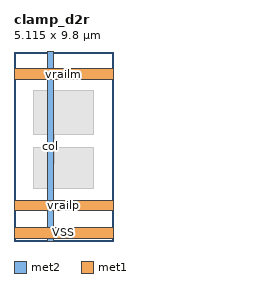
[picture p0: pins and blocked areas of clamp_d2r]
MACRO clamp_d2r
  CLASS BLOCK ;
  ORIGIN 0.000 0.000 ;
  SIZE 5.115 BY 9.800 ;
  SYMMETRY X Y ;
  PIN col
    DIRECTION INOUT ;
    USE SIGNAL ;
    PORT
      LAYER met2 ;
        RECT 1.740 0.000 2.060 9.800 ;
    END
  END col
  PIN vrailp
    DIRECTION INOUT ;
    USE SIGNAL ;
    PORT
      LAYER met1 ;
        RECT 0.000 1.550 5.115 2.100 ;
    END
  END vrailp
  PIN vrailm
    DIRECTION INOUT ;
    USE SIGNAL ;
    PORT
      LAYER met1 ;
        RECT 0.000 8.330 5.115 8.880 ;
    END
  END vrailm
  PIN VSS
    DIRECTION INOUT ;
    USE GROUND ;
    PORT
      LAYER met1 ;
        RECT 0.000 0.150 5.115 0.700 ;
    END
  END VSS
  OBS
    LAYER li1 ;
      RECT 0.250 0.260 4.865 0.590 ;
      RECT 1.000 1.620 4.115 2.040 ;
      RECT 1.000 2.700 4.115 4.805 ;
      RECT 1.735 3.995 2.065 6.305 ;
      RECT 1.000 5.495 4.115 7.745 ;
      RECT 1.000 8.440 4.115 8.770 ;
    LAYER met1 ;
      RECT 0.000 0.150 5.115 0.700 ;
      RECT 0.000 1.550 5.115 2.100 ;
      RECT 1.720 4.970 2.080 5.330 ;
      RECT 0.000 8.330 5.115 8.880 ;
    LAYER met2 ;
      RECT 1.740 0.000 2.060 9.800 ;
  END
END clamp_d2r
